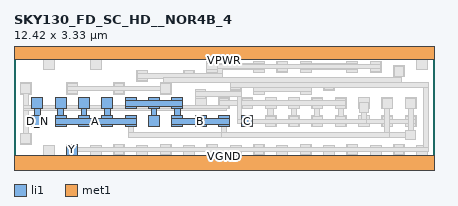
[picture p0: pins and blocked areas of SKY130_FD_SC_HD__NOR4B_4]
MACRO SKY130_FD_SC_HD__NOR4B_4
 CLASS CORE ;
 FOREIGN SKY130_FD_SC_HD__NOR4B_4 0 0 ;
 SIZE 12.42 BY 3.33 ;
 ORIGIN 0 0 ;
 SYMMETRY X Y R90 ;
 SITE unit ;
  PIN VPWR
   DIRECTION INOUT ;
   USE POWER ;
   SHAPE ABUTMENT ;
    PORT
     CLASS CORE ;
       LAYER li1 ;
        RECT 0.00000000 3.09000000 12.42000000 3.57000000 ;
       LAYER met1 ;
        RECT 0.00000000 3.09000000 12.42000000 3.57000000 ;
    END
  END VPWR

  PIN VGND
   DIRECTION INOUT ;
   USE POWER ;
   SHAPE ABUTMENT ;
    PORT
     CLASS CORE ;
       LAYER li1 ;
        RECT 0.00000000 -0.24000000 12.42000000 0.24000000 ;
       LAYER met1 ;
        RECT 0.00000000 -0.24000000 12.42000000 0.24000000 ;
    END
  END VGND

  PIN Y
   DIRECTION INOUT ;
   USE SIGNAL ;
   SHAPE ABUTMENT ;
    PORT
     CLASS CORE ;
       LAYER li1 ;
        RECT 1.56000000 0.26000000 1.89000000 0.59000000 ;
    END
  END Y

  PIN B
   DIRECTION INOUT ;
   USE SIGNAL ;
   SHAPE ABUTMENT ;
    PORT
     CLASS CORE ;
       LAYER li1 ;
        RECT 4.66500000 1.09500000 4.99500000 1.17500000 ;
        RECT 5.35500000 1.09500000 5.68500000 1.17500000 ;
        RECT 6.04500000 1.09500000 6.37500000 1.17500000 ;
        RECT 4.66500000 1.17500000 6.37500000 1.34500000 ;
        RECT 3.97500000 1.09500000 4.30500000 1.42500000 ;
        RECT 4.66500000 1.34500000 4.99500000 1.42500000 ;
        RECT 5.35500000 1.34500000 5.68500000 1.42500000 ;
        RECT 6.04500000 1.34500000 6.37500000 1.42500000 ;
        RECT 4.05500000 1.42500000 4.22500000 1.63500000 ;
        RECT 4.74500000 1.42500000 4.91500000 1.63500000 ;
        RECT 3.28500000 1.63500000 3.61500000 1.71500000 ;
        RECT 3.97500000 1.63500000 4.30500000 1.71500000 ;
        RECT 4.66500000 1.63500000 4.99500000 1.71500000 ;
        RECT 3.28500000 1.71500000 4.99500000 1.88500000 ;
        RECT 3.28500000 1.88500000 3.61500000 1.96500000 ;
        RECT 3.97500000 1.88500000 4.30500000 1.96500000 ;
        RECT 4.66500000 1.88500000 4.99500000 1.96500000 ;
    END
  END B

  PIN C
   DIRECTION INOUT ;
   USE SIGNAL ;
   SHAPE ABUTMENT ;
    PORT
     CLASS CORE ;
       LAYER li1 ;
        RECT 6.73500000 1.09500000 7.06500000 1.42500000 ;
    END
  END C

  PIN A
   DIRECTION INOUT ;
   USE SIGNAL ;
   SHAPE ABUTMENT ;
    PORT
     CLASS CORE ;
       LAYER li1 ;
        RECT 1.21500000 1.09500000 1.54500000 1.17500000 ;
        RECT 1.90500000 1.09500000 2.23500000 1.17500000 ;
        RECT 2.59500000 1.09500000 2.92500000 1.17500000 ;
        RECT 3.28500000 1.09500000 3.61500000 1.17500000 ;
        RECT 1.21500000 1.17500000 3.61500000 1.34500000 ;
        RECT 1.21500000 1.34500000 1.54500000 1.42500000 ;
        RECT 1.90500000 1.34500000 2.23500000 1.42500000 ;
        RECT 2.59500000 1.34500000 2.92500000 1.42500000 ;
        RECT 3.28500000 1.34500000 3.61500000 1.42500000 ;
        RECT 1.29500000 1.42500000 1.46500000 1.63500000 ;
        RECT 1.98500000 1.42500000 2.15500000 1.63500000 ;
        RECT 2.67500000 1.42500000 2.84500000 1.63500000 ;
        RECT 1.21500000 1.63500000 1.54500000 1.96500000 ;
        RECT 1.90500000 1.63500000 2.23500000 1.96500000 ;
        RECT 2.59500000 1.63500000 2.92500000 1.96500000 ;
    END
  END A

  PIN D_N
   DIRECTION INOUT ;
   USE SIGNAL ;
   SHAPE ABUTMENT ;
    PORT
     CLASS CORE ;
       LAYER li1 ;
        RECT 0.52500000 1.09500000 0.85500000 1.42500000 ;
        RECT 0.60500000 1.42500000 0.77500000 1.63500000 ;
        RECT 0.52500000 1.63500000 0.85500000 1.96500000 ;
    END
  END D_N

 OBS
    LAYER polycont ;
     RECT 4.05500000 1.17500000 4.22500000 1.34500000 ;
     RECT 4.74500000 1.17500000 4.91500000 1.34500000 ;
     RECT 5.43500000 1.17500000 5.60500000 1.34500000 ;
     RECT 6.12500000 1.17500000 6.29500000 1.34500000 ;
     RECT 3.36500000 1.71500000 3.53500000 1.88500000 ;
     RECT 4.05500000 1.71500000 4.22500000 1.88500000 ;
     RECT 4.74500000 1.71500000 4.91500000 1.88500000 ;
     RECT 10.95500000 1.71500000 11.12500000 1.88500000 ;
     RECT 8.88500000 1.17500000 9.05500000 1.34500000 ;
     RECT 9.57500000 1.17500000 9.74500000 1.34500000 ;
     RECT 10.95500000 1.17500000 11.12500000 1.34500000 ;
     RECT 11.64500000 1.17500000 11.81500000 1.34500000 ;
     RECT 6.12500000 1.71500000 6.29500000 1.88500000 ;
     RECT 6.81500000 1.71500000 6.98500000 1.88500000 ;
     RECT 8.88500000 1.71500000 9.05500000 1.88500000 ;
     RECT 9.57500000 1.71500000 9.74500000 1.88500000 ;
     RECT 0.60500000 1.17500000 0.77500000 1.34500000 ;
     RECT 0.60500000 1.71500000 0.77500000 1.88500000 ;
     RECT 6.81500000 1.17500000 6.98500000 1.34500000 ;
     RECT 7.50500000 1.17500000 7.67500000 1.34500000 ;
     RECT 8.19500000 1.17500000 8.36500000 1.34500000 ;
     RECT 10.26500000 1.17500000 10.43500000 1.34500000 ;
     RECT 5.43500000 1.71500000 5.60500000 1.88500000 ;
     RECT 7.50500000 1.71500000 7.67500000 1.88500000 ;
     RECT 8.19500000 1.71500000 8.36500000 1.88500000 ;
     RECT 10.26500000 1.71500000 10.43500000 1.88500000 ;
     RECT 1.29500000 1.17500000 1.46500000 1.34500000 ;
     RECT 1.98500000 1.17500000 2.15500000 1.34500000 ;
     RECT 2.67500000 1.17500000 2.84500000 1.34500000 ;
     RECT 3.36500000 1.17500000 3.53500000 1.34500000 ;
     RECT 1.29500000 1.71500000 1.46500000 1.88500000 ;
     RECT 1.98500000 1.71500000 2.15500000 1.88500000 ;
     RECT 2.67500000 1.71500000 2.84500000 1.88500000 ;
     RECT 11.64500000 1.71500000 11.81500000 1.88500000 ;

    LAYER pdiffc ;
     RECT 6.47000000 2.25500000 6.64000000 2.42500000 ;
     RECT 9.23000000 2.25500000 9.40000000 2.42500000 ;
     RECT 0.26000000 2.15000000 0.43000000 2.32000000 ;
     RECT 0.95000000 2.86000000 1.12000000 3.03000000 ;
     RECT 2.33000000 2.86000000 2.50000000 3.03000000 ;
     RECT 11.99000000 2.86000000 12.16000000 3.03000000 ;
     RECT 7.16000000 2.15000000 7.33000000 2.32000000 ;
     RECT 8.54000000 2.15000000 8.71000000 2.32000000 ;
     RECT 5.78000000 2.79500000 5.95000000 2.96500000 ;
     RECT 7.16000000 2.79500000 7.33000000 2.96500000 ;
     RECT 8.54000000 2.79500000 8.71000000 2.96500000 ;
     RECT 9.92000000 2.79500000 10.09000000 2.96500000 ;
     RECT 1.64000000 2.15000000 1.81000000 2.32000000 ;
     RECT 3.02000000 2.15000000 3.19000000 2.32000000 ;
     RECT 4.40000000 2.15000000 4.57000000 2.32000000 ;
     RECT 11.30000000 2.66000000 11.47000000 2.83000000 ;
     RECT 3.71000000 2.52500000 3.88000000 2.69500000 ;
     RECT 5.09000000 2.52500000 5.26000000 2.69500000 ;
     RECT 7.85000000 2.79500000 8.02000000 2.96500000 ;
     RECT 10.61000000 2.79500000 10.78000000 2.96500000 ;

    LAYER ndiffc ;
     RECT 1.64000000 0.34000000 1.81000000 0.51000000 ;
     RECT 3.02000000 0.34000000 3.19000000 0.51000000 ;
     RECT 4.40000000 0.34000000 4.57000000 0.51000000 ;
     RECT 5.78000000 0.34000000 5.95000000 0.51000000 ;
     RECT 7.16000000 0.34000000 7.33000000 0.51000000 ;
     RECT 8.54000000 0.34000000 8.71000000 0.51000000 ;
     RECT 9.92000000 0.34000000 10.09000000 0.51000000 ;
     RECT 11.30000000 0.34000000 11.47000000 0.51000000 ;
     RECT 0.26000000 0.66000000 0.43000000 0.83000000 ;
     RECT 0.95000000 0.30000000 1.12000000 0.47000000 ;
     RECT 2.33000000 0.30000000 2.50000000 0.47000000 ;
     RECT 3.71000000 0.30000000 3.88000000 0.47000000 ;
     RECT 5.09000000 0.30000000 5.26000000 0.47000000 ;
     RECT 6.47000000 0.30000000 6.64000000 0.47000000 ;
     RECT 7.85000000 0.30000000 8.02000000 0.47000000 ;
     RECT 9.23000000 0.30000000 9.40000000 0.47000000 ;
     RECT 10.61000000 0.30000000 10.78000000 0.47000000 ;
     RECT 11.99000000 0.30000000 12.16000000 0.47000000 ;

    LAYER li1 ;
     RECT 6.04500000 1.09500000 6.37500000 1.17500000 ;
     RECT 4.66500000 1.17500000 6.37500000 1.34500000 ;
     RECT 6.04500000 1.34500000 6.37500000 1.42500000 ;
     RECT 3.28500000 1.63500000 3.61500000 1.71500000 ;
     RECT 3.97500000 1.63500000 4.30500000 1.71500000 ;
     RECT 4.66500000 1.63500000 4.99500000 1.71500000 ;
     RECT 10.87500000 1.63500000 11.20500000 1.96500000 ;
     RECT 6.04500000 1.63500000 6.37500000 1.96500000 ;
     RECT 6.73500000 1.63500000 7.06500000 1.96500000 ;
     RECT 8.80500000 1.63500000 9.13500000 1.96500000 ;
     RECT 9.49500000 1.63500000 9.82500000 1.96500000 ;
     RECT 0.00000000 3.09000000 12.42000000 3.57000000 ;
     RECT 5.70000000 2.79500000 7.41000000 2.96500000 ;
     RECT 0.52500000 1.63500000 0.85500000 1.96500000 ;
     RECT 7.42500000 1.63500000 7.75500000 1.96500000 ;
     RECT 8.11500000 1.63500000 8.44500000 1.96500000 ;
     RECT 10.18500000 1.63500000 10.51500000 1.96500000 ;
     RECT 5.35500000 1.63500000 5.68500000 1.96500000 ;
     RECT 0.00000000 -0.24000000 12.42000000 0.24000000 ;
     RECT 1.21500000 1.63500000 1.54500000 1.96500000 ;
     RECT 1.90500000 1.63500000 2.23500000 1.96500000 ;
     RECT 2.59500000 1.63500000 2.92500000 1.96500000 ;
     RECT 11.56500000 1.63500000 11.89500000 1.96500000 ;
     RECT 8.46000000 2.71500000 8.79000000 2.79500000 ;
     RECT 9.84000000 2.71500000 10.17000000 2.79500000 ;
     RECT 8.46000000 2.79500000 10.17000000 2.96500000 ;
     RECT 8.46000000 2.96500000 8.79000000 3.04500000 ;
     RECT 9.84000000 2.96500000 10.17000000 3.04500000 ;
     RECT 11.22000000 2.58000000 11.55000000 2.91000000 ;
     RECT 11.91000000 2.78000000 12.24000000 3.09000000 ;
     RECT 6.39000000 2.17500000 6.72000000 2.50500000 ;
     RECT 7.08000000 2.07000000 7.41000000 2.15000000 ;
     RECT 8.46000000 2.07000000 8.79000000 2.15000000 ;
     RECT 7.08000000 2.15000000 8.79000000 2.32000000 ;
     RECT 7.08000000 2.32000000 7.41000000 2.40000000 ;
     RECT 8.46000000 2.32000000 8.79000000 2.40000000 ;
     RECT 7.08000000 2.71500000 7.41000000 2.79500000 ;
     RECT 9.15000000 2.17500000 9.48000000 2.50500000 ;
     RECT 7.08000000 2.96500000 7.41000000 3.04500000 ;
     RECT 7.77000000 2.71500000 8.10000000 3.04500000 ;
     RECT 10.53000000 2.71500000 10.86000000 3.04500000 ;
     RECT 3.28500000 1.71500000 4.99500000 1.88500000 ;
     RECT 5.70000000 2.96500000 6.03000000 3.04500000 ;
     RECT 3.28500000 1.88500000 3.61500000 1.96500000 ;
     RECT 3.97500000 1.88500000 4.30500000 1.96500000 ;
     RECT 0.18000000 2.07000000 0.51000000 2.40000000 ;
     RECT 5.43500000 1.96500000 5.60500000 2.15500000 ;
     RECT 0.87000000 2.78000000 1.20000000 3.09000000 ;
     RECT 2.25000000 2.78000000 2.58000000 3.09000000 ;
     RECT 5.70000000 2.71500000 6.03000000 2.79500000 ;
     RECT 1.56000000 2.07000000 1.89000000 2.40000000 ;
     RECT 2.94000000 2.07000000 3.27000000 2.40000000 ;
     RECT 3.63000000 2.44500000 3.96000000 2.77500000 ;
     RECT 5.01000000 2.44500000 5.34000000 2.77500000 ;
     RECT 4.32000000 2.07000000 4.65000000 2.40000000 ;
     RECT 4.66500000 1.88500000 4.99500000 1.96500000 ;
     RECT 1.56000000 0.26000000 1.89000000 0.59000000 ;
     RECT 2.94000000 0.26000000 3.27000000 0.59000000 ;
     RECT 4.32000000 0.26000000 4.65000000 0.59000000 ;
     RECT 5.70000000 0.26000000 6.03000000 0.59000000 ;
     RECT 3.97500000 1.09500000 4.30500000 1.42500000 ;
     RECT 4.66500000 1.34500000 4.99500000 1.42500000 ;
     RECT 0.87000000 0.24000000 1.20000000 0.55000000 ;
     RECT 2.25000000 0.24000000 2.58000000 0.55000000 ;
     RECT 3.63000000 0.24000000 3.96000000 0.55000000 ;
     RECT 5.01000000 0.24000000 5.34000000 0.55000000 ;
     RECT 1.21500000 1.09500000 1.54500000 1.17500000 ;
     RECT 1.90500000 1.09500000 2.23500000 1.17500000 ;
     RECT 2.59500000 1.09500000 2.92500000 1.17500000 ;
     RECT 3.28500000 1.09500000 3.61500000 1.17500000 ;
     RECT 1.21500000 1.17500000 3.61500000 1.34500000 ;
     RECT 1.21500000 1.34500000 1.54500000 1.42500000 ;
     RECT 1.90500000 1.34500000 2.23500000 1.42500000 ;
     RECT 2.59500000 1.34500000 2.92500000 1.42500000 ;
     RECT 3.28500000 1.34500000 3.61500000 1.42500000 ;
     RECT 1.29500000 1.42500000 1.46500000 1.63500000 ;
     RECT 1.98500000 1.42500000 2.15500000 1.63500000 ;
     RECT 2.67500000 1.42500000 2.84500000 1.63500000 ;
     RECT 0.18000000 0.58000000 0.51000000 0.91000000 ;
     RECT 5.35500000 1.34500000 5.68500000 1.42500000 ;
     RECT 4.66500000 1.09500000 4.99500000 1.17500000 ;
     RECT 4.05500000 1.42500000 4.22500000 1.63500000 ;
     RECT 4.74500000 1.42500000 4.91500000 1.63500000 ;
     RECT 0.52500000 1.09500000 0.85500000 1.42500000 ;
     RECT 0.60500000 1.42500000 0.77500000 1.63500000 ;
     RECT 5.35500000 1.09500000 5.68500000 1.17500000 ;
     RECT 7.50500000 1.42500000 7.67500000 1.63500000 ;
     RECT 11.56500000 1.09500000 11.89500000 1.42500000 ;
     RECT 8.11500000 1.09500000 8.44500000 1.42500000 ;
     RECT 8.19500000 1.42500000 8.36500000 1.63500000 ;
     RECT 11.22000000 0.26000000 11.55000000 0.59000000 ;
     RECT 10.18500000 1.09500000 10.51500000 1.42500000 ;
     RECT 10.26500000 1.42500000 10.43500000 1.63500000 ;
     RECT 7.08000000 0.26000000 7.41000000 0.59000000 ;
     RECT 8.46000000 0.26000000 8.79000000 0.59000000 ;
     RECT 9.84000000 0.26000000 10.17000000 0.59000000 ;
     RECT 8.80500000 1.09500000 9.13500000 1.42500000 ;
     RECT 9.49500000 1.09500000 9.82500000 1.42500000 ;
     RECT 10.87500000 1.09500000 11.20500000 1.42500000 ;
     RECT 6.73500000 1.09500000 7.06500000 1.42500000 ;
     RECT 7.42500000 1.09500000 7.75500000 1.42500000 ;
     RECT 6.39000000 0.24000000 6.72000000 0.55000000 ;
     RECT 7.77000000 0.24000000 8.10000000 0.55000000 ;
     RECT 9.15000000 0.24000000 9.48000000 0.55000000 ;
     RECT 10.53000000 0.24000000 10.86000000 0.55000000 ;
     RECT 11.91000000 0.24000000 12.24000000 0.55000000 ;

    LAYER viali ;
     RECT 6.12500000 1.17500000 6.29500000 1.34500000 ;
     RECT 10.95500000 1.71500000 11.12500000 1.88500000 ;
     RECT 1.64000000 0.34000000 1.81000000 0.51000000 ;
     RECT 3.02000000 0.34000000 3.19000000 0.51000000 ;
     RECT 4.40000000 0.34000000 4.57000000 0.51000000 ;
     RECT 5.78000000 0.34000000 5.95000000 0.51000000 ;
     RECT 7.16000000 0.34000000 7.33000000 0.51000000 ;
     RECT 8.54000000 0.34000000 8.71000000 0.51000000 ;
     RECT 9.92000000 0.34000000 10.09000000 0.51000000 ;
     RECT 11.30000000 0.34000000 11.47000000 0.51000000 ;
     RECT 6.47000000 2.25500000 6.64000000 2.42500000 ;
     RECT 9.23000000 2.25500000 9.40000000 2.42500000 ;
     RECT 0.26000000 0.66000000 0.43000000 0.83000000 ;
     RECT 8.88500000 1.17500000 9.05500000 1.34500000 ;
     RECT 9.57500000 1.17500000 9.74500000 1.34500000 ;
     RECT 10.95500000 1.17500000 11.12500000 1.34500000 ;
     RECT 11.64500000 1.17500000 11.81500000 1.34500000 ;
     RECT 6.12500000 1.71500000 6.29500000 1.88500000 ;
     RECT 6.81500000 1.71500000 6.98500000 1.88500000 ;
     RECT 8.88500000 1.71500000 9.05500000 1.88500000 ;
     RECT 9.57500000 1.71500000 9.74500000 1.88500000 ;
     RECT 0.26000000 2.15000000 0.43000000 2.32000000 ;
     RECT 11.99000000 3.24500000 12.16000000 3.41500000 ;
     RECT 1.64000000 2.15000000 1.81000000 2.32000000 ;
     RECT 3.02000000 2.15000000 3.19000000 2.32000000 ;
     RECT 4.40000000 2.15000000 4.57000000 2.32000000 ;
     RECT 11.30000000 2.66000000 11.47000000 2.83000000 ;
     RECT 6.81500000 1.17500000 6.98500000 1.34500000 ;
     RECT 7.50500000 1.17500000 7.67500000 1.34500000 ;
     RECT 8.19500000 1.17500000 8.36500000 1.34500000 ;
     RECT 10.26500000 1.58000000 10.43500000 1.75000000 ;
     RECT 5.43500000 1.98500000 5.60500000 2.15500000 ;
     RECT 6.47000000 -0.08500000 6.64000000 0.08500000 ;
     RECT 3.36500000 1.17500000 3.53500000 1.34500000 ;
     RECT 11.64500000 1.71500000 11.81500000 1.88500000 ;
     RECT 3.71000000 2.52500000 3.88000000 2.69500000 ;
     RECT 5.09000000 2.52500000 5.26000000 2.69500000 ;
     RECT 7.85000000 2.79500000 8.02000000 2.96500000 ;
     RECT 10.61000000 2.79500000 10.78000000 2.96500000 ;

    LAYER met1 ;
     RECT 6.06500000 1.11500000 6.35500000 1.40500000 ;
     RECT 10.89500000 1.65500000 11.18500000 1.94500000 ;
     RECT 1.58000000 0.28000000 1.87000000 0.35500000 ;
     RECT 2.96000000 0.28000000 3.25000000 0.35500000 ;
     RECT 4.34000000 0.28000000 4.63000000 0.35500000 ;
     RECT 5.72000000 0.28000000 6.01000000 0.35500000 ;
     RECT 7.10000000 0.28000000 7.39000000 0.35500000 ;
     RECT 8.48000000 0.28000000 8.77000000 0.35500000 ;
     RECT 9.86000000 0.28000000 10.15000000 0.35500000 ;
     RECT 11.24000000 0.28000000 11.53000000 0.35500000 ;
     RECT 1.58000000 0.35500000 12.26000000 0.49500000 ;
     RECT 1.58000000 0.49500000 1.87000000 0.57000000 ;
     RECT 2.96000000 0.49500000 3.25000000 0.57000000 ;
     RECT 4.34000000 0.49500000 4.63000000 0.57000000 ;
     RECT 5.72000000 0.49500000 6.01000000 0.57000000 ;
     RECT 7.10000000 0.49500000 7.39000000 0.57000000 ;
     RECT 8.48000000 0.49500000 8.77000000 0.57000000 ;
     RECT 9.86000000 0.49500000 10.15000000 0.57000000 ;
     RECT 11.24000000 0.49500000 11.53000000 0.57000000 ;
     RECT 6.41000000 2.19500000 6.70000000 2.27000000 ;
     RECT 9.17000000 2.19500000 9.46000000 2.27000000 ;
     RECT 12.12000000 0.49500000 12.26000000 2.27000000 ;
     RECT 6.41000000 2.27000000 12.26000000 2.41000000 ;
     RECT 6.41000000 2.41000000 6.70000000 2.48500000 ;
     RECT 9.17000000 2.41000000 9.46000000 2.48500000 ;
     RECT 0.20000000 0.60000000 0.49000000 0.89000000 ;
     RECT 9.51500000 1.11500000 9.80500000 1.19000000 ;
     RECT 10.89500000 1.11500000 11.18500000 1.19000000 ;
     RECT 11.58500000 1.11500000 11.87500000 1.19000000 ;
     RECT 9.51500000 1.19000000 11.87500000 1.33000000 ;
     RECT 8.82500000 1.11500000 9.11500000 1.40500000 ;
     RECT 9.51500000 1.33000000 9.80500000 1.40500000 ;
     RECT 10.89500000 1.33000000 11.18500000 1.40500000 ;
     RECT 11.58500000 1.33000000 11.87500000 1.40500000 ;
     RECT 0.27500000 0.89000000 0.41500000 1.59500000 ;
     RECT 0.27500000 1.59500000 6.28000000 1.65500000 ;
     RECT 8.90000000 1.40500000 9.04000000 1.65500000 ;
     RECT 9.59000000 1.40500000 9.73000000 1.65500000 ;
     RECT 0.27500000 1.65500000 6.35500000 1.73000000 ;
     RECT 6.75500000 1.65500000 7.04500000 1.73000000 ;
     RECT 8.82500000 1.65500000 9.11500000 1.73000000 ;
     RECT 9.51500000 1.65500000 9.80500000 1.73000000 ;
     RECT 0.27500000 1.73000000 9.80500000 1.73500000 ;
     RECT 6.06500000 1.73500000 9.80500000 1.87000000 ;
     RECT 6.06500000 1.87000000 6.35500000 1.94500000 ;
     RECT 6.75500000 1.87000000 7.04500000 1.94500000 ;
     RECT 8.82500000 1.87000000 9.11500000 1.94500000 ;
     RECT 9.51500000 1.87000000 9.80500000 1.94500000 ;
     RECT 0.27500000 1.73500000 0.41500000 2.09000000 ;
     RECT 0.20000000 2.09000000 0.49000000 2.38000000 ;
     RECT 0.00000000 3.09000000 12.42000000 3.57000000 ;
     RECT 1.58000000 2.09000000 1.87000000 2.16500000 ;
     RECT 2.96000000 2.09000000 3.25000000 2.16500000 ;
     RECT 4.34000000 2.09000000 4.63000000 2.16500000 ;
     RECT 1.58000000 2.16500000 4.63000000 2.30500000 ;
     RECT 1.58000000 2.30500000 1.87000000 2.38000000 ;
     RECT 2.96000000 2.30500000 3.25000000 2.38000000 ;
     RECT 4.34000000 2.30500000 4.63000000 2.38000000 ;
     RECT 11.24000000 2.60000000 11.53000000 2.89000000 ;
     RECT 6.75500000 1.11500000 7.04500000 1.19000000 ;
     RECT 7.44500000 1.11500000 7.73500000 1.19000000 ;
     RECT 8.13500000 1.11500000 8.42500000 1.19000000 ;
     RECT 6.75500000 1.19000000 8.42500000 1.33000000 ;
     RECT 6.75500000 1.33000000 7.04500000 1.40500000 ;
     RECT 7.44500000 1.33000000 7.73500000 1.40500000 ;
     RECT 8.13500000 1.33000000 8.42500000 1.40500000 ;
     RECT 10.20500000 1.52000000 10.49500000 1.81000000 ;
     RECT 5.37500000 1.92500000 5.66500000 2.21500000 ;
     RECT 0.00000000 -0.24000000 12.42000000 0.24000000 ;
     RECT 11.58500000 0.71000000 11.87500000 0.78500000 ;
     RECT 3.38000000 0.78500000 11.87500000 0.92500000 ;
     RECT 11.58500000 0.92500000 11.87500000 1.00000000 ;
     RECT 3.38000000 0.92500000 3.52000000 1.11500000 ;
     RECT 3.30500000 1.11500000 3.59500000 1.40500000 ;
     RECT 11.58500000 1.65500000 11.87500000 1.94500000 ;
     RECT 3.65000000 2.46500000 3.94000000 2.54000000 ;
     RECT 5.03000000 2.46500000 5.32000000 2.54000000 ;
     RECT 3.65000000 2.54000000 6.16500000 2.68000000 ;
     RECT 3.65000000 2.68000000 3.94000000 2.75500000 ;
     RECT 5.03000000 2.68000000 5.32000000 2.75500000 ;
     RECT 6.02500000 2.68000000 6.16500000 2.81000000 ;
     RECT 7.79000000 2.73500000 8.08000000 2.81000000 ;
     RECT 10.55000000 2.73500000 10.84000000 2.81000000 ;
     RECT 6.02500000 2.81000000 10.84000000 2.95000000 ;
     RECT 7.79000000 2.95000000 8.08000000 3.02500000 ;
     RECT 10.55000000 2.95000000 10.84000000 3.02500000 ;

    LAYER via ;
     RECT 6.12500000 1.17500000 6.29500000 1.34500000 ;
     RECT 10.95500000 1.71500000 11.12500000 1.88500000 ;
     RECT 4.40000000 2.15000000 4.57000000 2.32000000 ;
     RECT 11.30000000 2.66000000 11.47000000 2.83000000 ;
     RECT 8.19500000 1.17500000 8.36500000 1.34500000 ;
     RECT 10.26500000 1.58000000 10.43500000 1.75000000 ;
     RECT 5.43500000 1.98500000 5.60500000 2.15500000 ;
     RECT 11.64500000 0.77000000 11.81500000 0.94000000 ;
     RECT 11.64500000 1.71500000 11.81500000 1.88500000 ;

    LAYER met2 ;
     RECT 4.55500000 2.38000000 4.63000000 2.40500000 ;
     RECT 11.24000000 2.54500000 11.31500000 2.60000000 ;
     RECT 6.14000000 0.78500000 11.11000000 0.92500000 ;
     RECT 6.14000000 0.92500000 6.28000000 1.11500000 ;
     RECT 6.06500000 1.11500000 6.35500000 1.40500000 ;
     RECT 10.97000000 0.92500000 11.11000000 1.65500000 ;
     RECT 10.89500000 1.65500000 11.18500000 1.94500000 ;
     RECT 4.34000000 2.09000000 4.63000000 2.38000000 ;
     RECT 4.41500000 2.38000000 4.55500000 2.40500000 ;
     RECT 4.41500000 2.40500000 11.45500000 2.54500000 ;
     RECT 11.31500000 2.54500000 11.45500000 2.60000000 ;
     RECT 11.24000000 2.60000000 11.53000000 2.89000000 ;
     RECT 8.13500000 1.11500000 8.42500000 1.19000000 ;
     RECT 6.60000000 1.19000000 10.42000000 1.33000000 ;
     RECT 8.13500000 1.33000000 8.42500000 1.40500000 ;
     RECT 10.28000000 1.33000000 10.42000000 1.52000000 ;
     RECT 10.20500000 1.52000000 10.49500000 1.81000000 ;
     RECT 5.37500000 1.92500000 5.66500000 2.00000000 ;
     RECT 6.60000000 1.33000000 6.74000000 2.00000000 ;
     RECT 5.37500000 2.00000000 6.74000000 2.14000000 ;
     RECT 5.37500000 2.14000000 5.66500000 2.21500000 ;
     RECT 11.58500000 0.71000000 11.87500000 1.00000000 ;
     RECT 11.66000000 1.00000000 11.80000000 1.65500000 ;
     RECT 11.58500000 1.65500000 11.87500000 1.94500000 ;

    LAYER via2 ;


    LAYER met3 ;


 END
END SKY130_FD_SC_HD__NOR4B_4
